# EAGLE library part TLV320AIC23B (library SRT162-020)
audio dac/adc

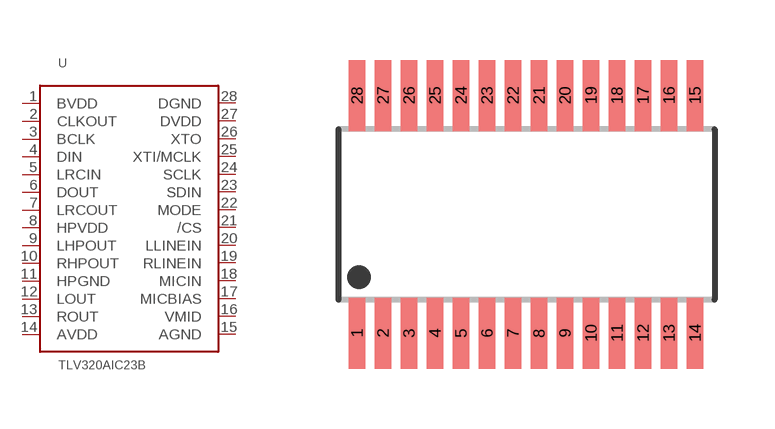
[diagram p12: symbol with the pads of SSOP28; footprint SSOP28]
Designator prefix U

## TLV320AIC23B  [SSOP28]
1  BVDD  pas
2  CLKOUT  pas
3  BCLK  pas
4  DIN  pas
5  LRCIN  pas
6  DOUT  pas
7  LRCOUT  pas
8  HPVDD  pas
9  LHPOUT  pas
10  RHPOUT  pas
11  HPGND  pas
12  LOUT  pas
13  ROUT  pas
14  AVDD  pas
15  AGND  pas
16  VMID  pas
17  MICBIAS  pas
18  MICIN  pas
19  RLINEIN  pas
20  LLINEIN  pas
21  /CS  pas
22  MODE  pas
23  SDIN  pas
24  SCLK  pas
25  XTI/MCLK  pas
26  XTO  pas
27  DVDD  pas
28  DGND  pas

## Footprint SSOP28 (pad centres in mm)
0.65mm pitch 28 pin
smd 0.42 x 1.78: 1 -4.26,-3.005; 2 -3.61,-3.005; 3 -2.96,-3.005; 4 -2.31,-3.005; 5 -1.66,-3.005; 6 -1.01,-3.005; 7 -0.36,-3.005; 8 0.29,-3.005; 9 0.94,-3.005; 10 1.59,-3.005; 11 2.24,-3.005; 12 2.89,-3.005; 13 3.54,-3.005; 14 4.19,-3.005; 15 4.19,2.945; 16 3.54,2.945; 17 2.89,2.945; 18 2.24,2.945; 19 1.59,2.945; 20 0.94,2.945; 21 0.29,2.945; 22 -0.36,2.945; 23 -1.01,2.945; 24 -1.66,2.945; 25 -2.31,2.945; 26 -2.96,2.945; 27 -3.61,2.945; 28 -4.26,2.945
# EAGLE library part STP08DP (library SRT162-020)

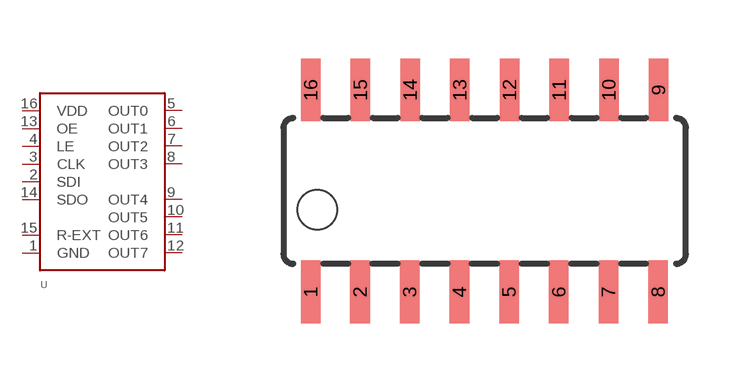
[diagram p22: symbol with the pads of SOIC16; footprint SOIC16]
Designator prefix U

## STP08DPM  [SOIC16]
1  GND  pwr
2  SDI  in
3  CLK  in
4  LE  in
5  OUT0  pas
6  OUT1  pas
7  OUT2  pas
8  OUT3  pas
9  OUT4  pas
10  OUT5  pas
11  OUT6  pas
12  OUT7  pas
13  OE  in
14  SDO  out
15  R-EXT  pas
16  VDD  pwr

## Footprint SOIC16 (pad centres in mm)
smd 0.5 x 1.6: 1 -4.445,-2.583; 2 -3.185,-2.583; 3 -1.915,-2.583; 4 -0.645,-2.583; 5 0.625,-2.583; 6 1.895,-2.583; 7 3.165,-2.583; 8 4.435,-2.583; 9 4.445,2.583; 10 3.175,2.583; 11 1.905,2.583; 12 0.635,2.583; 13 -0.635,2.583; 14 -1.905,2.583; 15 -3.175,2.583; 16 -4.445,2.583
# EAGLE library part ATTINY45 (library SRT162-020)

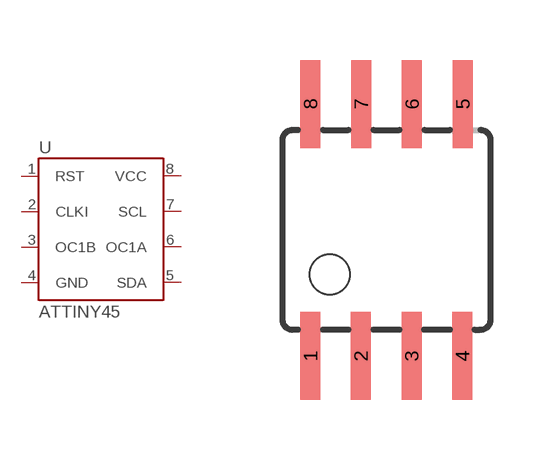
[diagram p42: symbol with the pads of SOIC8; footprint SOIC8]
Designator prefix U

## ATTINY45SOIC  [SOIC8]
1  RST  pas
2  CLKI  pas
3  OC1B  pas
4  GND  pwr
5  SDA  pas
6  OC1A  pas
7  SCL  pas
8  VCC  in

## Footprint SOIC8 (pad centres in mm)
smd 0.5 x 2.2: 1 -1.905,-3.154; 2 -0.645,-3.154; 3 0.625,-3.154; 4 1.895,-3.154; 5 1.905,3.154; 6 0.635,3.154; 7 -0.635,3.154; 8 -1.905,3.154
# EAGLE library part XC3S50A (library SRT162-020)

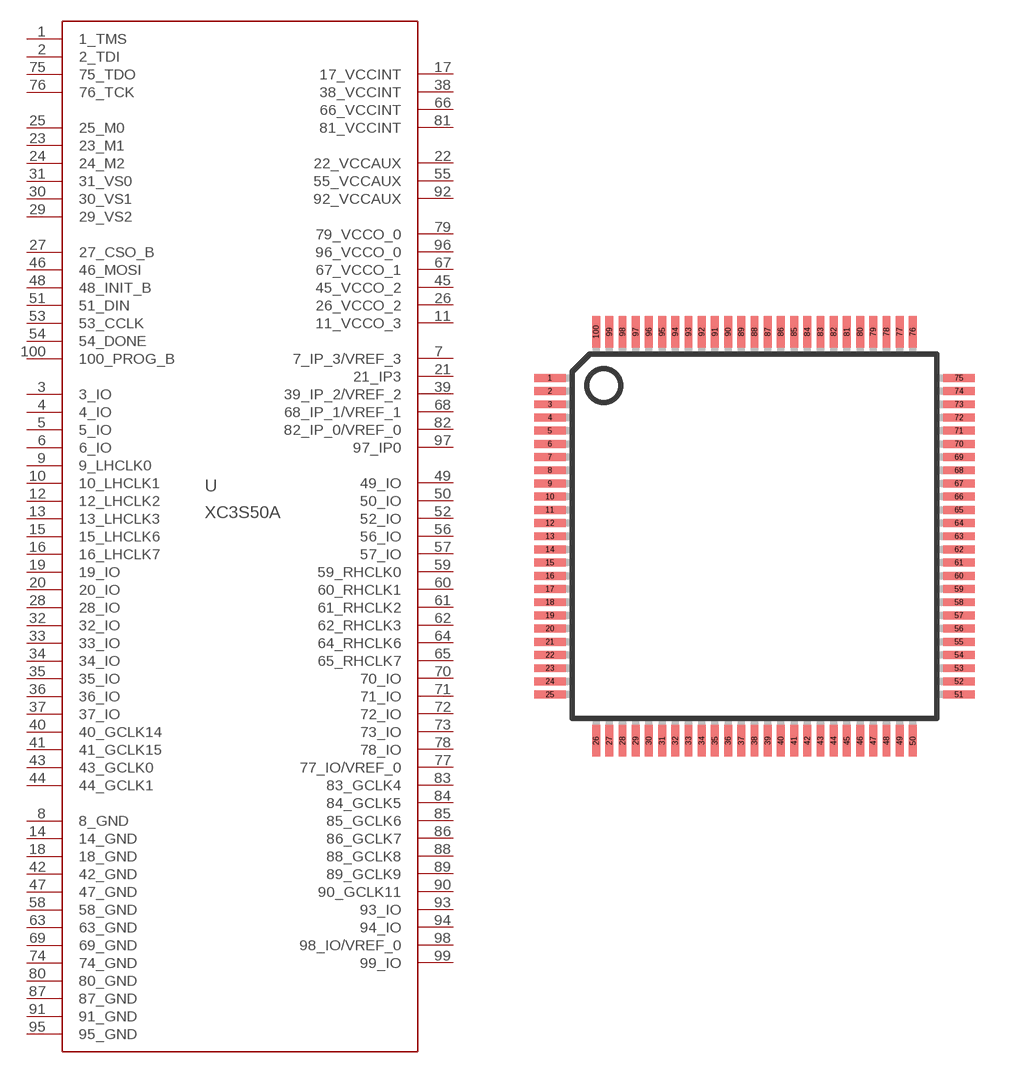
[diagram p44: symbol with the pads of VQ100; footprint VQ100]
Designator prefix U

## XC3S50AVQ100  [VQ100]
1  1_TMS  in
2  2_TDI  in
3  3_IO
4  4_IO
5  5_IO
6  6_IO
7  7_IP_3/VREF_3
8  8_GND  pwr
9  9_LHCLK0
10  10_LHCLK1
11  11_VCCO_3  pwr
12  12_LHCLK2
13  13_LHCLK3
14  14_GND  pwr
15  15_LHCLK6
16  16_LHCLK7
17  17_VCCINT  pwr
18  18_GND  pwr
19  19_IO
20  20_IO
21  21_IP3
22  22_VCCAUX  pwr
23  23_M1  in
24  24_M2  in
25  25_M0  in
26  26_VCCO_2  pwr
27  27_CSO_B
28  28_IO
29  29_VS2
30  30_VS1
31  31_VS0
32  32_IO
33  33_IO
34  34_IO
35  35_IO
36  36_IO
37  37_IO
38  38_VCCINT  pwr
39  39_IP_2/VREF_2
40  40_GCLK14
41  41_GCLK15
42  42_GND  pwr
43  43_GCLK0
44  44_GCLK1
45  45_VCCO_2  pwr
46  46_MOSI
47  47_GND  pwr
48  48_INIT_B
49  49_IO
50  50_IO
51  51_DIN
52  52_IO
53  53_CCLK
54  54_DONE
55  55_VCCAUX  pwr
56  56_IO
57  57_IO
58  58_GND  pwr
59  59_RHCLK0
60  60_RHCLK1
61  61_RHCLK2
62  62_RHCLK3
63  63_GND  pwr
64  64_RHCLK6
65  65_RHCLK7
66  66_VCCINT  pwr
67  67_VCCO_1  pwr
68  68_IP_1/VREF_1
69  69_GND  pwr
70  70_IO
71  71_IO
72  72_IO
73  73_IO
74  74_GND  pwr
75  75_TDO  out
76  76_TCK  in
77  77_IO/VREF_0
78  78_IO
79  79_VCCO_0  pwr
80  80_GND  pwr
81  81_VCCINT  pwr
82  82_IP_0/VREF_0
83  83_GCLK4
84  84_GCLK5
85  85_GCLK6
86  86_GCLK7
87  87_GND  pwr
88  88_GCLK8
89  89_GCLK9
90  90_GCLK11
91  91_GND  pwr
92  92_VCCAUX  pwr
93  93_IO
94  94_IO
95  95_GND  pwr
96  96_VCCO_0  pwr
97  97_IP0
98  98_IO/VREF_0
99  99_IO
100  100_PROG_B  in

## Footprint VQ100 (pad centres in mm)
smd 1.2 x 0.3: 1 -7.75,6; 2 -7.75,5.5; 3 -7.75,5; 4 -7.75,4.5; 5 -7.75,4; 6 -7.75,3.5; 7 -7.75,3; 8 -7.75,2.5; 9 -7.75,2; 10 -7.75,1.5; 11 -7.75,1; 12 -7.75,0.5; 13 -7.75,0; 14 -7.75,-0.5; 15 -7.75,-1; 16 -7.75,-1.5; 17 -7.75,-2; 18 -7.75,-2.5; 19 -7.75,-3; 20 -7.75,-3.5; 21 -7.75,-4; 22 -7.75,-4.5; 23 -7.75,-5; 24 -7.75,-5.5; 25 -7.75,-6; 51 7.75,-6; 52 7.75,-5.5; 53 7.75,-5; 54 7.75,-4.5; 55 7.75,-4; 56 7.75,-3.5; 57 7.75,-3; 58 7.75,-2.5; 59 7.75,-2; 60 7.75,-1.5; 61 7.75,-1; 62 7.75,-0.5; 63 7.75,0; 64 7.75,0.5; 65 7.75,1; 66 7.75,1.5; 67 7.75,2; 68 7.75,2.5; 69 7.75,3; 70 7.75,3.5; 71 7.75,4; 72 7.75,4.5; 73 7.75,5; 74 7.75,5.5; 75 7.75,6
smd 0.3 x 1.2: 26 -6,-7.75; 27 -5.5,-7.75; 28 -5,-7.75; 29 -4.5,-7.75; 30 -4,-7.75; 31 -3.5,-7.75; 32 -3,-7.75; 33 -2.5,-7.75; 34 -2,-7.75; 35 -1.5,-7.75; 36 -1,-7.75; 37 -0.5,-7.75; 38 0,-7.75; 39 0.5,-7.75; 40 1,-7.75; 41 1.5,-7.75; 42 2,-7.75; 43 2.5,-7.75; 44 3,-7.75; 45 3.5,-7.75; 46 4,-7.75; 47 4.5,-7.75; 48 5,-7.75; 49 5.5,-7.75; 50 6,-7.75; 76 6,7.75; 77 5.5,7.75; 78 5,7.75; 79 4.5,7.75; 80 4,7.75; 81 3.5,7.75; 82 3,7.75; 83 2.5,7.75; 84 2,7.75; 85 1.5,7.75; 86 1,7.75; 87 0.5,7.75; 88 0,7.75; 89 -0.5,7.75; 90 -1,7.75; 91 -1.5,7.75; 92 -2,7.75; 93 -2.5,7.75; 94 -3,7.75; 95 -3.5,7.75; 96 -4,7.75; 97 -4.5,7.75; 98 -5,7.75; 99 -5.5,7.75; 100 -6,7.75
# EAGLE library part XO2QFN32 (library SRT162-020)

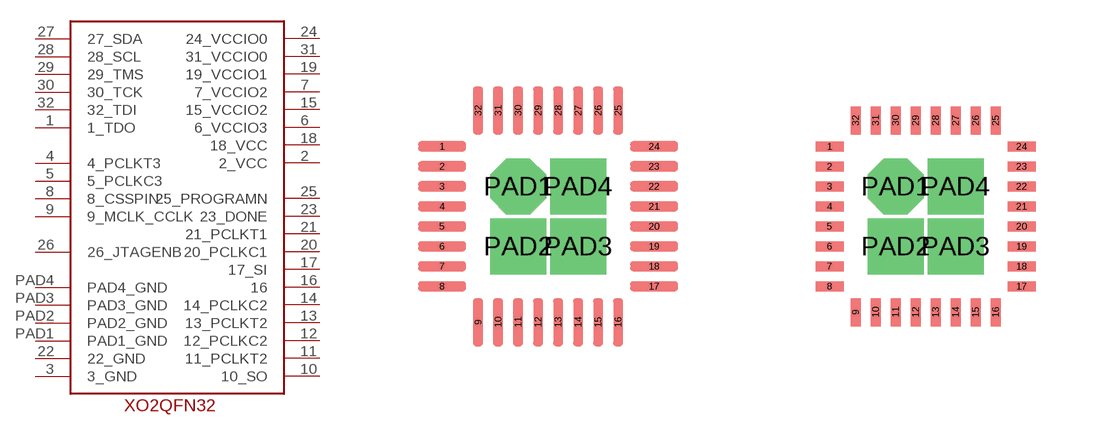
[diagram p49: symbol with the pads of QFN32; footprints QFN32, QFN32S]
Designator prefix U

## XO2QFN32  [QFN32]
1  1_TDO
2  2_VCC
3  3_GND
4  4_PCLKT3
5  5_PCLKC3
6  6_VCCIO3
7  7_VCCIO2
8  8_CSSPIN
9  9_MCLK_CCLK
10  10_SO
11  11_PCLKT2
12  12_PCLKC2
13  13_PCLKT2
14  14_PCLKC2
15  15_VCCIO2
16  16
17  17_SI
18  18_VCC
19  19_VCCIO1
20  20_PCLKC1
21  21_PCLKT1
22  22_GND
23  23_DONE
24  24_VCCIO0
25  25_PROGRAMN
26  26_JTAGENB
27  27_SDA
28  28_SCL
29  29_TMS
30  30_TCK
31  31_VCCIO0
32  32_TDI
PAD1  PAD1_GND
PAD2  PAD2_GND
PAD3  PAD3_GND
PAD4  PAD4_GND

## XO2QFN32S  [QFN32S]
Pads as for QFN32

## Footprint QFN32 (pad centres in mm)
smd 1.2 x 0.25: 1 -2.65,1.75; 2 -2.65,1.25; 3 -2.65,0.75; 4 -2.65,0.25; 5 -2.65,-0.25; 6 -2.65,-0.75; 7 -2.65,-1.25; 8 -2.65,-1.75; 17 2.65,-1.75; 18 2.65,-1.25; 19 2.65,-0.75; 20 2.65,-0.25; 21 2.65,0.25; 22 2.65,0.75; 23 2.65,1.25; 24 2.65,1.75
smd 0.25 x 1.2: 9 -1.75,-2.65; 10 -1.25,-2.65; 11 -0.75,-2.65; 12 -0.25,-2.65; 13 0.25,-2.65; 14 0.75,-2.65; 15 1.25,-2.65; 16 1.75,-2.65; 25 1.75,2.65; 26 1.25,2.65; 27 0.75,2.65; 28 0.25,2.65; 29 -0.25,2.65; 30 -0.75,2.65; 31 -1.25,2.65; 32 -1.75,2.65
drill 0.6 pad 1.4 octagon: PAD1 -0.75,0.75
drill 0.6 pad 1.4 square: PAD2 -0.75,-0.75; PAD3 0.75,-0.75; PAD4 0.75,0.75

## Footprint QFN32S (pad centres in mm)
smd 0.7 x 0.25: 1 -2.4,1.75; 2 -2.4,1.25; 3 -2.4,0.75; 4 -2.4,0.25; 5 -2.4,-0.25; 6 -2.4,-0.75; 7 -2.4,-1.25; 8 -2.4,-1.75; 17 2.4,-1.75; 18 2.4,-1.25; 19 2.4,-0.75; 20 2.4,-0.25; 21 2.4,0.25; 22 2.4,0.75; 23 2.4,1.25; 24 2.4,1.75
smd 0.25 x 0.7: 9 -1.75,-2.4; 10 -1.25,-2.4; 11 -0.75,-2.4; 12 -0.25,-2.4; 13 0.25,-2.4; 14 0.75,-2.4; 15 1.25,-2.4; 16 1.75,-2.4; 25 1.75,2.4; 26 1.25,2.4; 27 0.75,2.4; 28 0.25,2.4; 29 -0.25,2.4; 30 -0.75,2.4; 31 -1.25,2.4; 32 -1.75,2.4
drill 0.6 pad 1.4 octagon: PAD1 -0.75,0.75
drill 0.6 pad 1.4 square: PAD2 -0.75,-0.75; PAD3 0.75,-0.75; PAD4 0.75,0.75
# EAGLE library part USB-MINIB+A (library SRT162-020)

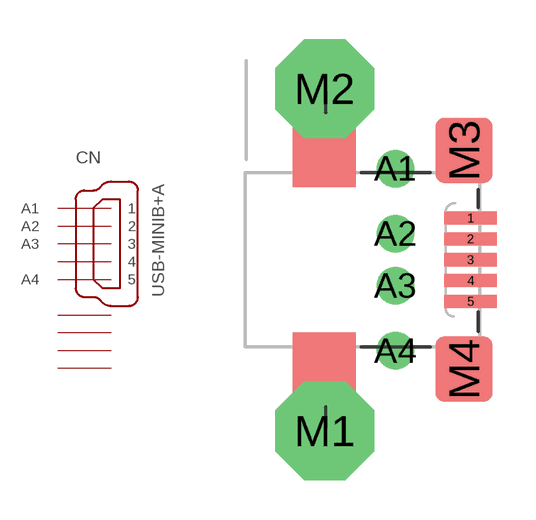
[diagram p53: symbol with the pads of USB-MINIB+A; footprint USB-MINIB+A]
Designator prefix CN

## USB-MINIB+A  [USB-MINIB+A]
1  1  in
2  2  in
3  3  in
4  4  in
5  5  in
A1  A1  in
A2  A2  in
A3  A3  in
A4  A4  in
M1  GND  pwr
M2  GND  pwr
M3  GND  pwr
M4  GND  pwr

## Footprint USB-MINIB+A (pad centres in mm)
smd 2 x 0.5: 1 2.25,1.6; 2 2.25,0.8; 3 2.25,0; 4 2.25,-0.8; 5 2.25,-1.6
drill 0.93: A1 -0.635,3.5; A2 -0.635,1; A3 -0.635,-1; A4 -0.635,-3.5
drill 2.4 pad 3.81 octagon: M1 -3.345,-6.57; M2 -3.345,6.57
smd 2.2 x 2.5: M3 2,4.2; M4 2,-4.2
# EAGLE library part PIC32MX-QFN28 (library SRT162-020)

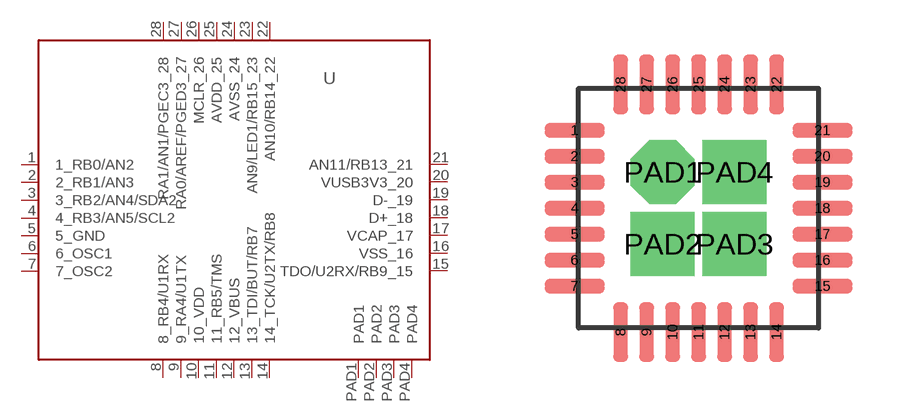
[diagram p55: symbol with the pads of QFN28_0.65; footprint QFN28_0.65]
Designator prefix U

## PIC32MX-QFN28  [QFN28_0.65]
1  1_RB0/AN2  pas
2  2_RB1/AN3  pas
3  3_RB2/AN4/SDA2  pas
4  4_RB3/AN5/SCL2  pas
5  5_GND  pwr
6  6_OSC1  pas
7  7_OSC2  pas
8  8_RB4/U1RX  pas
9  9_RA4/U1TX  pas
10  10_VDD  pwr
11  11_RB5/TMS  pas
12  12_VBUS  pas
13  13_TDI/BUT/RB7  pas
14  14_TCK/U2TX/RB8  pas
15  TDO/U2RX/RB9_15  pas
16  VSS_16  pwr
17  VCAP_17  sup
18  D+_18  pas
19  D-_19  pas
20  VUSB3V3_20  pwr
21  AN11/RB13_21  pas
22  AN10/RB14_22  pas
23  AN9/LED1/RB15_23  pas
24  AVSS_24  pwr
25  AVDD_25  pwr
26  MCLR_26  pas
27  RA0/AREF/PGED3_27  pas
28  RA1/AN1/PGEC3_28  pas
PAD1  PAD1  pas
PAD2  PAD2  pas
PAD3  PAD3  pas
PAD4  PAD4  pas

## Footprint QFN28_0.65 (pad centres in mm)
smd 1.5 x 0.37: 1 -3.1,1.95; 2 -3.1,1.3; 3 -3.1,0.65; 4 -3.1,0; 5 -3.1,-0.65; 6 -3.1,-1.3; 7 -3.1,-1.95; 15 3.1,-1.95; 16 3.1,-1.3; 17 3.1,-0.65; 18 3.1,0; 19 3.1,0.65; 20 3.1,1.3; 21 3.1,1.95
smd 0.37 x 1.5: 8 -1.95,-3.1; 9 -1.3,-3.1; 10 -0.65,-3.1; 11 0,-3.1; 12 0.65,-3.1; 13 1.3,-3.1; 14 1.95,-3.1; 22 1.95,3.1; 23 1.3,3.1; 24 0.65,3.1; 25 0,3.1; 26 -0.65,3.1; 27 -1.3,3.1; 28 -1.95,3.1
drill 0.6 pad 1.6 octagon: PAD1 -0.9,0.9
drill 0.6 pad 1.6 square: PAD2 -0.9,-0.9; PAD3 0.9,-0.9; PAD4 0.9,0.9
